VERSION 5.7 ;
  NOWIREEXTENSIONATPIN ON ;
  DIVIDERCHAR "/" ;
  BUSBITCHARS "[]" ;
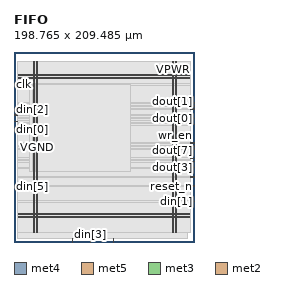
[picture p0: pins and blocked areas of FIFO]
MACRO FIFO
  CLASS BLOCK ;
  FOREIGN FIFO ;
  ORIGIN 0.000 0.000 ;
  SIZE 198.765 BY 209.485 ;
  PIN VGND
    DIRECTION INOUT ;
    USE GROUND ;
    PORT
      LAYER met4 ;
        RECT 24.340 10.640 25.940 198.800 ;
    END
    PORT
      LAYER met4 ;
        RECT 177.940 10.640 179.540 198.800 ;
    END
    PORT
      LAYER met5 ;
        RECT 5.280 30.030 193.440 31.630 ;
    END
    PORT
      LAYER met5 ;
        RECT 5.280 183.210 193.440 184.810 ;
    END
  END VGND
  PIN VPWR
    DIRECTION INOUT ;
    USE POWER ;
    PORT
      LAYER met4 ;
        RECT 21.040 10.640 22.640 198.800 ;
    END
    PORT
      LAYER met4 ;
        RECT 174.640 10.640 176.240 198.800 ;
    END
    PORT
      LAYER met5 ;
        RECT 5.280 26.730 193.440 28.330 ;
    END
    PORT
      LAYER met5 ;
        RECT 5.280 179.910 193.440 181.510 ;
    END
  END VPWR
  PIN clk
    DIRECTION INPUT ;
    USE SIGNAL ;
    ANTENNAGATEAREA 0.852000 ;
    PORT
      LAYER met3 ;
        RECT 0.000 173.440 4.000 174.040 ;
    END
  END clk
  PIN din[0]
    DIRECTION INPUT ;
    USE SIGNAL ;
    ANTENNAGATEAREA 0.213000 ;
    PORT
      LAYER met3 ;
        RECT 0.000 132.640 4.000 133.240 ;
    END
  END din[0]
  PIN din[1]
    DIRECTION INPUT ;
    USE SIGNAL ;
    ANTENNAGATEAREA 0.159000 ;
    PORT
      LAYER met3 ;
        RECT 194.765 44.240 198.765 44.840 ;
    END
  END din[1]
  PIN din[2]
    DIRECTION INPUT ;
    USE SIGNAL ;
    ANTENNAGATEAREA 0.159000 ;
    PORT
      LAYER met3 ;
        RECT 0.000 146.240 4.000 146.840 ;
    END
  END din[2]
  PIN din[3]
    DIRECTION INPUT ;
    USE SIGNAL ;
    ANTENNAGATEAREA 0.213000 ;
    PORT
      LAYER met2 ;
        RECT 83.810 0.000 84.090 4.000 ;
    END
  END din[3]
  PIN din[4]
    DIRECTION INPUT ;
    USE SIGNAL ;
    ANTENNAGATEAREA 0.213000 ;
    PORT
      LAYER met3 ;
        RECT 0.000 139.440 4.000 140.040 ;
    END
  END din[4]
  PIN din[5]
    DIRECTION INPUT ;
    USE SIGNAL ;
    ANTENNAGATEAREA 0.213000 ;
    PORT
      LAYER met3 ;
        RECT 0.000 61.240 4.000 61.840 ;
    END
  END din[5]
  PIN din[6]
    DIRECTION INPUT ;
    USE SIGNAL ;
    ANTENNAGATEAREA 0.213000 ;
    PORT
      LAYER met2 ;
        RECT 64.490 0.000 64.770 4.000 ;
    END
  END din[6]
  PIN din[7]
    DIRECTION INPUT ;
    USE SIGNAL ;
    ANTENNAGATEAREA 0.213000 ;
    PORT
      LAYER met2 ;
        RECT 109.570 0.000 109.850 4.000 ;
    END
  END din[7]
  PIN dout[0]
    DIRECTION OUTPUT ;
    USE SIGNAL ;
    ANTENNADIFFAREA 0.445500 ;
    PORT
      LAYER met3 ;
        RECT 194.765 136.040 198.765 136.640 ;
    END
  END dout[0]
  PIN dout[1]
    DIRECTION OUTPUT ;
    USE SIGNAL ;
    ANTENNADIFFAREA 0.445500 ;
    PORT
      LAYER met3 ;
        RECT 194.765 146.240 198.765 146.840 ;
    END
  END dout[1]
  PIN dout[2]
    DIRECTION OUTPUT ;
    USE SIGNAL ;
    ANTENNADIFFAREA 0.445500 ;
    PORT
      LAYER met3 ;
        RECT 194.765 153.040 198.765 153.640 ;
    END
  END dout[2]
  PIN dout[3]
    DIRECTION OUTPUT ;
    USE SIGNAL ;
    ANTENNADIFFAREA 0.445500 ;
    PORT
      LAYER met3 ;
        RECT 194.765 81.640 198.765 82.240 ;
    END
  END dout[3]
  PIN dout[4]
    DIRECTION OUTPUT ;
    USE SIGNAL ;
    ANTENNADIFFAREA 0.445500 ;
    PORT
      LAYER met3 ;
        RECT 194.765 149.640 198.765 150.240 ;
    END
  END dout[4]
  PIN dout[5]
    DIRECTION OUTPUT ;
    USE SIGNAL ;
    ANTENNADIFFAREA 0.445500 ;
    PORT
      LAYER met3 ;
        RECT 194.765 71.440 198.765 72.040 ;
    END
  END dout[5]
  PIN dout[6]
    DIRECTION OUTPUT ;
    USE SIGNAL ;
    ANTENNADIFFAREA 0.445500 ;
    PORT
      LAYER met3 ;
        RECT 194.765 129.240 198.765 129.840 ;
    END
  END dout[6]
  PIN dout[7]
    DIRECTION OUTPUT ;
    USE SIGNAL ;
    ANTENNADIFFAREA 0.445500 ;
    PORT
      LAYER met3 ;
        RECT 194.765 91.840 198.765 92.440 ;
    END
  END dout[7]
  PIN empty
    DIRECTION OUTPUT ;
    USE SIGNAL ;
    ANTENNADIFFAREA 0.445500 ;
    PORT
      LAYER met3 ;
        RECT 194.765 102.040 198.765 102.640 ;
    END
  END empty
  PIN full
    DIRECTION OUTPUT ;
    USE SIGNAL ;
    ANTENNADIFFAREA 0.445500 ;
    PORT
      LAYER met3 ;
        RECT 194.765 105.440 198.765 106.040 ;
    END
  END full
  PIN rd_en
    DIRECTION INPUT ;
    USE SIGNAL ;
    ANTENNAGATEAREA 0.213000 ;
    PORT
      LAYER met3 ;
        RECT 194.765 88.440 198.765 89.040 ;
    END
  END rd_en
  PIN reset_n
    DIRECTION INPUT ;
    USE SIGNAL ;
    ANTENNAGATEAREA 0.196500 ;
    PORT
      LAYER met3 ;
        RECT 194.765 61.240 198.765 61.840 ;
    END
  END reset_n
  PIN wr_en
    DIRECTION INPUT ;
    USE SIGNAL ;
    ANTENNAGATEAREA 0.196500 ;
    PORT
      LAYER met3 ;
        RECT 194.765 108.840 198.765 109.440 ;
    END
  END wr_en
  OBS
      LAYER nwell ;
        RECT 5.330 10.795 193.390 198.750 ;
      LAYER li1 ;
        RECT 5.520 10.795 193.200 198.645 ;
      LAYER met1 ;
        RECT 4.210 10.640 193.200 198.800 ;
      LAYER met2 ;
        RECT 4.230 4.280 191.730 198.745 ;
        RECT 4.230 4.000 64.210 4.280 ;
        RECT 65.050 4.000 83.530 4.280 ;
        RECT 84.370 4.000 109.290 4.280 ;
        RECT 110.130 4.000 191.730 4.280 ;
      LAYER met3 ;
        RECT 3.990 174.440 194.765 198.725 ;
        RECT 4.400 173.040 194.765 174.440 ;
        RECT 3.990 154.040 194.765 173.040 ;
        RECT 3.990 152.640 194.365 154.040 ;
        RECT 3.990 150.640 194.765 152.640 ;
        RECT 3.990 149.240 194.365 150.640 ;
        RECT 3.990 147.240 194.765 149.240 ;
        RECT 4.400 145.840 194.365 147.240 ;
        RECT 3.990 140.440 194.765 145.840 ;
        RECT 4.400 139.040 194.765 140.440 ;
        RECT 3.990 137.040 194.765 139.040 ;
        RECT 3.990 135.640 194.365 137.040 ;
        RECT 3.990 133.640 194.765 135.640 ;
        RECT 4.400 132.240 194.765 133.640 ;
        RECT 3.990 130.240 194.765 132.240 ;
        RECT 3.990 128.840 194.365 130.240 ;
        RECT 3.990 109.840 194.765 128.840 ;
        RECT 3.990 108.440 194.365 109.840 ;
        RECT 3.990 106.440 194.765 108.440 ;
        RECT 3.990 105.040 194.365 106.440 ;
        RECT 3.990 103.040 194.765 105.040 ;
        RECT 3.990 101.640 194.365 103.040 ;
        RECT 3.990 92.840 194.765 101.640 ;
        RECT 3.990 91.440 194.365 92.840 ;
        RECT 3.990 89.440 194.765 91.440 ;
        RECT 3.990 88.040 194.365 89.440 ;
        RECT 3.990 82.640 194.765 88.040 ;
        RECT 3.990 81.240 194.365 82.640 ;
        RECT 3.990 72.440 194.765 81.240 ;
        RECT 3.990 71.040 194.365 72.440 ;
        RECT 3.990 62.240 194.765 71.040 ;
        RECT 4.400 60.840 194.365 62.240 ;
        RECT 3.990 45.240 194.765 60.840 ;
        RECT 3.990 43.840 194.365 45.240 ;
        RECT 3.990 10.715 194.765 43.840 ;
      LAYER met4 ;
        RECT 16.855 77.695 20.640 173.905 ;
        RECT 23.040 77.695 23.940 173.905 ;
        RECT 26.340 77.695 128.505 173.905 ;
  END
END FIFO
END LIBRARY

